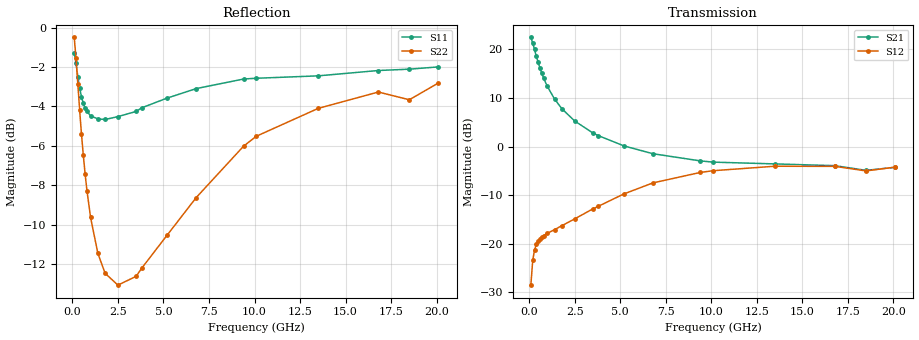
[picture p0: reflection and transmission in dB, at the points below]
!  Infineon Technologies AG
! BFR380L3 , PF131585-7, No.6, Th 09.10.01, soldered on pcb-board, measured with PP GSG850
!  Vce=0.75 V,  Ic=4.0 mA
! Common Emitter S-Parameters:  15. November 2001
#  GHz  S  MA  R  50
! f  S11  S21  S12  S22
! GHz  Mag  Ang  Mag  Ang  Mag  Ang  Mag  Ang
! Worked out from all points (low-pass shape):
!   201 points, 100 MHz to 20.1 GHz, reference 50 ohm
!   highest |S21| = 22.45 dB at 100 MHz (marker M1); lowest = -4.9 dB at 18.5 GHz (marker M2)
!   |S21| within 3 dB of the highest: start of sweep to 337.9 MHz
!   lowest |S11| = -4.7 dB at 1.8 GHz (marker M3), VSWR 3.81, Z = 13.1 - j0.214 ohm
!   |S11| at or under -10 dB: nowhere
!   |S22| runs from -13.1 to -0.5 dB; largest |S21 - S12| = 13
!   S11 on the Smith chart (normalised r, x): 100 MHz: 1.01, -3.42; 400 MHz: 0.31, -0.85; 1 GHz: 0.27, -0.25; 3.8 GHz: 0.26, +0.33; 9.4 GHz: 0.34, +1.10; 20.1 GHz: 0.97, +2.58
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0.1  0.8619 -30.3  13.27 160.3  0.03762 74.4  0.944 -19.8
0.2  0.8115 -57.2  11.62 143.7  0.0675 60.7  0.8357 -36.3
0.3  0.7506 -79.0  9.965 130.9  0.08635 51.4  0.7175 -49.0
0.4  0.7018 -96.1  8.521 121.1  0.09864 45.1  0.6164 -58.7
0.5  0.6675 -109.8  7.337 113.4  0.1069 41.2  0.5363 -66.2
0.6  0.6417 -121.0  6.4 107.3  0.1131 38.5  0.474 -72.2
0.7  0.6238 -130.2  5.665 102.2  0.1177 36.7  0.4247 -77.2
0.8  0.6123 -137.7  5.061 97.8  0.1215 35.8  0.3857 -81.6
1  0.5971 -149.9  4.171 90.6  0.1281 35.0  0.3296 -88.8
1.4  0.5863 -167.2  3.083 79.4  0.1401 36.1  0.2671 -100.2
1.8  0.5843 -179.5  2.455 70.4  0.1535 38.0  0.2378 -109.4
2.5  0.5942 164.2  1.836 57.2  0.1803 41.4  0.222 -123.8
3.5  0.6124 146.0  1.382 41.9  0.2285 43.7  0.2337 -141.7
3.8  0.6254 141.6  1.297 38.0  0.243 43.7  0.2448 -147.8
5.2  0.6621 122.2  1.018 22.0  0.3256 39.8  0.2972 -169.5
6.8  0.6999 103.6  0.8444 8.8  0.4231 31.9  0.3703 165.5
9.400001  0.7402 81.4  0.7129 -4.7  0.5419 14.7  0.5 134.5
10.1  0.7435 76.5  0.6921 -7.6  0.5649 10.0  0.5298 126.9
13.5  0.754 58.7  0.6635 -21.4  0.628 -11.5  0.6235 96.6
16.8  0.7779 47.2  0.6364 -32.7  0.6261 -27.3  0.686 75.0
18.5  0.784 45.1  0.5695 -40.1  0.5622 -35.7  0.6557 69.6
20.1  0.7945 38.1  0.6124 -43.8  0.6147 -40.6  0.7233 58.9
